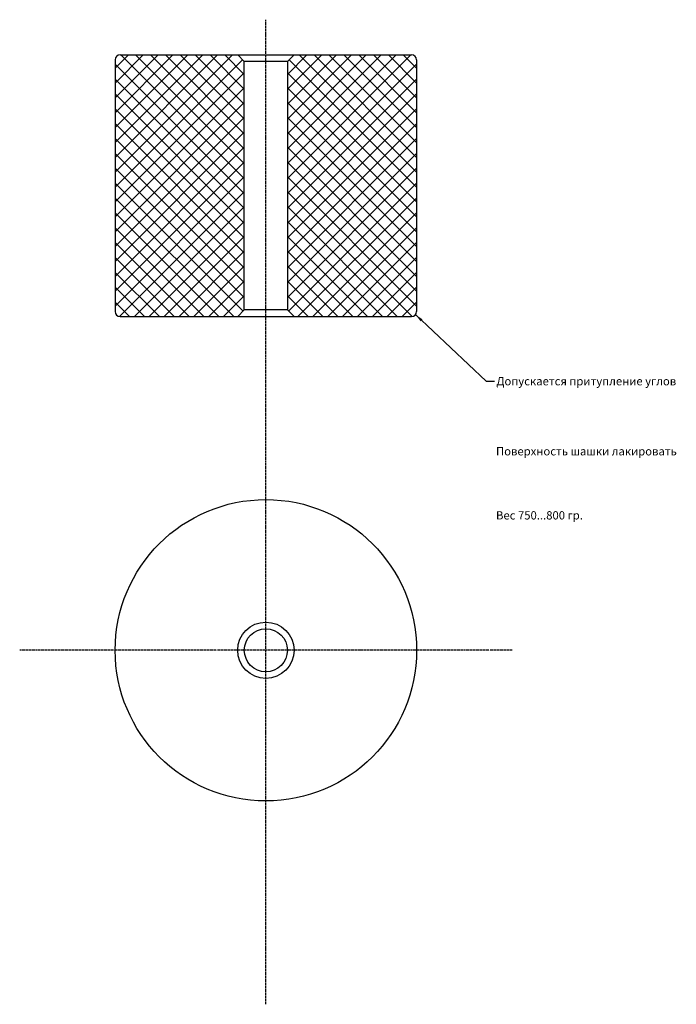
# Model space of a CAD drawing. Units: millimetres. Extents: x -74 to 124, y -108 to 189.
import ezdxf

# ---------------------------------------------------------------- set-up
doc = ezdxf.new("R2010")
doc.units = ezdxf.units.MM
doc.header["$LTSCALE"] = 0.2
doc.linetypes.add('ACAD_ISO10W100', pattern=[18, 12, -3, 0, -3])
doc.dimstyles.new('ISO-25', dxfattribs={"dimtxt": 2.5, "dimasz": 2.5, "dimexe": 1.25, "dimexo": 0.625, "dimtad": 1, "dimtxsty": 'Standard', "dimcen": 2.5, "dimadec": 0, "dimazin": 0, "dimtfac": 1, "dimtmove": 0, "dimatfit": 3, "dimfxl": 0, "dimarcsym": 0})

msp = doc.modelspace()

# ---------------------------------------------------------------- hatches: boundary and pattern name
at = {"lineweight": 15, "ltscale": 0.25}
h = msp.add_hatch(dxfattribs=at)
h.set_pattern_fill('ANSI37', style=0)
h.paths.add_polyline_path([(-6.5, 176.51), (-8.5, 178.51), (-44, 178.51, 0.414214), (-45.5, 177.01), (-45.5, 101.01, 0.414214), (-44, 99.51), (-8.5, 99.51), (-6.5, 101.51)])
h.paths.add_polyline_path([(45.5, 177.01, 0.414214), (44, 178.51), (8.5, 178.51), (6.5, 176.51), (6.5, 101.51), (8.5, 99.51), (44, 99.51, 0.414214), (45.5, 101.01)])

# ---------------------------------------------------------------- linework, layer by layer
at = {"color": 1, "linetype": 'ACAD_ISO10W100', "lineweight": 25, "ltscale": 0.25}
for p, q in [((0, 114.83), (0, 189.15)), ((0, 40.5), (0, 114.83)), ((0, -33.83), (0, 40.5)), ((0, -1.25), (-74.33, -1.25)), ((74.33, -1.25), (0, -1.25)), ((0, -108.15), (0, -33.83))]:
    msp.add_line(p, q, dxfattribs=at)
at = {"color": 7, "lineweight": 30, "ltscale": 0.25}
for p, q in [((-44, 178.51), (44, 178.51)), ((-6.5, 176.51), (-8.5, 178.51)), ((8.5, 178.51), (6.5, 176.51)), ((-45.5, 177.01), (-45.5, 101.01)), ((6.5, 176.51), (-6.5, 176.51)), ((-6.5, 101.51), (-6.5, 176.51)), ((6.5, 176.51), (6.5, 101.51)), ((45.5, 177.01), (45.5, 101.01)), ((-6.5, 101.51), (-8.5, 99.51)), ((6.5, 101.51), (-6.5, 101.51)), ((8.5, 99.51), (6.5, 101.51)), ((-44, 99.51), (44, 99.51))]:
    msp.add_line(p, q, dxfattribs=at)
for radius in [45.5, 8.5, 6.5]:
    msp.add_circle((0, -1.25), radius, dxfattribs=at)
for centre, start, end in [((-44, 177.01), 90, 180), ((44, 177.01), 0, 90), ((-44, 101.01), 180, 270), ((44, 101.01), 270, 0)]:
    msp.add_arc(centre, 1.5, start, end, dxfattribs=at)

# ---------------------------------------------------------------- texts
at = {"color": 7, "lineweight": 15, "ltscale": 0.25}
for s, p in [('Поверхность шашки лакировать', (69.5, 57.59)), ('Вес 750...800 гр.', (69.5, 38.24))]:
    msp.add_text(s, height=2.5, dxfattribs=at).set_placement(p)
at = {"color": 7, "lineweight": 15, "ltscale": 0.25, "insert": (69.62, 81.25), "char_height": 2.5, "attachment_point": 1}
msp.add_mtext('{\\fTahoma|b0|i0|c204|p32;Допускается притупление углов}', dxfattribs=at)

# ---------------------------------------------------------------- leaders
at = {"color": 7, "lineweight": 15, "ltscale": 0.25, "annotation_type": 0, "has_hookline": 1, "hookline_direction": 0, "text_width": 50.96}
msp.add_leader([(45.19, 100.09), (66.49, 80), (68.99, 80)], dimstyle='ISO-25', override={"dimgap": 0.625, "dimtad": 0}, dxfattribs=at)

doc.saveas('drawing.dxf')
